VERSION 5.7 ;
  NOWIREEXTENSIONATPIN ON ;
  DIVIDERCHAR "/" ;
  BUSBITCHARS "[]" ;
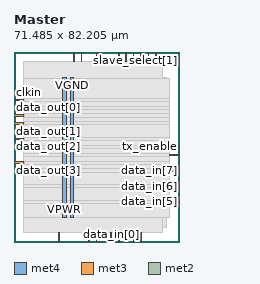
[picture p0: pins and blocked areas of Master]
MACRO Master
  CLASS BLOCK ;
  FOREIGN Master ;
  ORIGIN 0.000 0.000 ;
  SIZE 71.485 BY 82.205 ;
  PIN VGND
    DIRECTION INOUT ;
    USE GROUND ;
    PORT
      LAYER met4 ;
        RECT 24.340 10.640 25.940 70.960 ;
    END
  END VGND
  PIN VPWR
    DIRECTION INOUT ;
    USE POWER ;
    PORT
      LAYER met4 ;
        RECT 21.040 10.640 22.640 70.960 ;
    END
  END VPWR
  PIN clkin
    DIRECTION INPUT ;
    USE SIGNAL ;
    ANTENNAGATEAREA 0.852000 ;
    PORT
      LAYER met3 ;
        RECT 0.000 61.240 4.000 61.840 ;
    END
  END clkin
  PIN data_in[0]
    DIRECTION INPUT ;
    USE SIGNAL ;
    ANTENNAGATEAREA 0.196500 ;
    PORT
      LAYER met2 ;
        RECT 41.950 0.000 42.230 4.000 ;
    END
  END data_in[0]
  PIN data_in[1]
    DIRECTION INPUT ;
    USE SIGNAL ;
    ANTENNAGATEAREA 0.196500 ;
    PORT
      LAYER met2 ;
        RECT 51.610 0.000 51.890 4.000 ;
    END
  END data_in[1]
  PIN data_in[2]
    DIRECTION INPUT ;
    USE SIGNAL ;
    ANTENNAGATEAREA 0.196500 ;
    PORT
      LAYER met2 ;
        RECT 45.170 0.000 45.450 4.000 ;
    END
  END data_in[2]
  PIN data_in[3]
    DIRECTION INPUT ;
    USE SIGNAL ;
    ANTENNAGATEAREA 0.196500 ;
    PORT
      LAYER met2 ;
        RECT 48.390 0.000 48.670 4.000 ;
    END
  END data_in[3]
  PIN data_in[4]
    DIRECTION INPUT ;
    USE SIGNAL ;
    ANTENNAGATEAREA 0.196500 ;
    PORT
      LAYER met2 ;
        RECT 54.830 0.000 55.110 4.000 ;
    END
  END data_in[4]
  PIN data_in[5]
    DIRECTION INPUT ;
    USE SIGNAL ;
    ANTENNAGATEAREA 0.196500 ;
    PORT
      LAYER met3 ;
        RECT 67.485 17.040 71.485 17.640 ;
    END
  END data_in[5]
  PIN data_in[6]
    DIRECTION INPUT ;
    USE SIGNAL ;
    ANTENNAGATEAREA 0.196500 ;
    PORT
      LAYER met3 ;
        RECT 67.485 23.840 71.485 24.440 ;
    END
  END data_in[6]
  PIN data_in[7]
    DIRECTION INPUT ;
    USE SIGNAL ;
    ANTENNAGATEAREA 0.196500 ;
    PORT
      LAYER met3 ;
        RECT 67.485 30.640 71.485 31.240 ;
    END
  END data_in[7]
  PIN data_out[0]
    DIRECTION OUTPUT ;
    USE SIGNAL ;
    ANTENNADIFFAREA 0.445500 ;
    PORT
      LAYER met3 ;
        RECT 0.000 57.840 4.000 58.440 ;
    END
  END data_out[0]
  PIN data_out[1]
    DIRECTION OUTPUT ;
    USE SIGNAL ;
    ANTENNADIFFAREA 0.445500 ;
    PORT
      LAYER met3 ;
        RECT 0.000 44.240 4.000 44.840 ;
    END
  END data_out[1]
  PIN data_out[2]
    DIRECTION OUTPUT ;
    USE SIGNAL ;
    ANTENNADIFFAREA 0.445500 ;
    PORT
      LAYER met3 ;
        RECT 0.000 40.840 4.000 41.440 ;
    END
  END data_out[2]
  PIN data_out[3]
    DIRECTION OUTPUT ;
    USE SIGNAL ;
    ANTENNADIFFAREA 0.445500 ;
    PORT
      LAYER met3 ;
        RECT 0.000 30.640 4.000 31.240 ;
    END
  END data_out[3]
  PIN data_out[4]
    DIRECTION OUTPUT ;
    USE SIGNAL ;
    ANTENNADIFFAREA 0.445500 ;
    PORT
      LAYER met2 ;
        RECT 19.410 0.000 19.690 4.000 ;
    END
  END data_out[4]
  PIN data_out[5]
    DIRECTION OUTPUT ;
    USE SIGNAL ;
    ANTENNADIFFAREA 0.445500 ;
    PORT
      LAYER met3 ;
        RECT 0.000 34.040 4.000 34.640 ;
    END
  END data_out[5]
  PIN data_out[6]
    DIRECTION OUTPUT ;
    USE SIGNAL ;
    ANTENNADIFFAREA 0.445500 ;
    PORT
      LAYER met2 ;
        RECT 32.290 0.000 32.570 4.000 ;
    END
  END data_out[6]
  PIN data_out[7]
    DIRECTION OUTPUT ;
    USE SIGNAL ;
    ANTENNADIFFAREA 0.445500 ;
    PORT
      LAYER met2 ;
        RECT 35.510 0.000 35.790 4.000 ;
    END
  END data_out[7]
  PIN miso
    DIRECTION INPUT ;
    USE SIGNAL ;
    ANTENNAGATEAREA 0.196500 ;
    PORT
      LAYER met3 ;
        RECT 0.000 54.440 4.000 55.040 ;
    END
  END miso
  PIN mode[0]
    DIRECTION INPUT ;
    USE SIGNAL ;
    ANTENNAGATEAREA 0.196500 ;
    PORT
      LAYER met2 ;
        RECT 25.850 78.205 26.130 82.205 ;
    END
  END mode[0]
  PIN mode[1]
    DIRECTION INPUT ;
    USE SIGNAL ;
    ANTENNAGATEAREA 0.196500 ;
    PORT
      LAYER met2 ;
        RECT 29.070 78.205 29.350 82.205 ;
    END
  END mode[1]
  PIN mosi
    DIRECTION OUTPUT ;
    USE SIGNAL ;
    ANTENNADIFFAREA 0.445500 ;
    PORT
      LAYER met3 ;
        RECT 67.485 37.440 71.485 38.040 ;
    END
  END mosi
  PIN reset
    DIRECTION INPUT ;
    USE SIGNAL ;
    ANTENNAGATEAREA 0.196500 ;
    PORT
      LAYER met3 ;
        RECT 0.000 51.040 4.000 51.640 ;
    END
  END reset
  PIN sclk
    DIRECTION OUTPUT ;
    USE SIGNAL ;
    ANTENNADIFFAREA 0.445500 ;
    PORT
      LAYER met2 ;
        RECT 35.510 78.205 35.790 82.205 ;
    END
  END sclk
  PIN slave_select[0]
    DIRECTION OUTPUT ;
    USE SIGNAL ;
    ANTENNADIFFAREA 0.445500 ;
    PORT
      LAYER met2 ;
        RECT 45.170 78.205 45.450 82.205 ;
    END
  END slave_select[0]
  PIN slave_select[1]
    DIRECTION OUTPUT ;
    USE SIGNAL ;
    ANTENNADIFFAREA 0.445500 ;
    PORT
      LAYER met2 ;
        RECT 61.270 78.205 61.550 82.205 ;
    END
  END slave_select[1]
  PIN slave_select[2]
    DIRECTION OUTPUT ;
    USE SIGNAL ;
    ANTENNADIFFAREA 0.445500 ;
    PORT
      LAYER met2 ;
        RECT 54.830 78.205 55.110 82.205 ;
    END
  END slave_select[2]
  PIN slave_select[3]
    DIRECTION OUTPUT ;
    USE SIGNAL ;
    ANTENNADIFFAREA 0.445500 ;
    PORT
      LAYER met2 ;
        RECT 51.610 78.205 51.890 82.205 ;
    END
  END slave_select[3]
  PIN slave_select_in[0]
    DIRECTION INPUT ;
    USE SIGNAL ;
    ANTENNAGATEAREA 0.196500 ;
    PORT
      LAYER met2 ;
        RECT 58.050 78.205 58.330 82.205 ;
    END
  END slave_select_in[0]
  PIN slave_select_in[1]
    DIRECTION INPUT ;
    USE SIGNAL ;
    ANTENNAGATEAREA 0.196500 ;
    PORT
      LAYER met2 ;
        RECT 48.390 78.205 48.670 82.205 ;
    END
  END slave_select_in[1]
  PIN tx_enable
    DIRECTION INPUT ;
    USE SIGNAL ;
    ANTENNAGATEAREA 0.196500 ;
    PORT
      LAYER met3 ;
        RECT 67.485 40.840 71.485 41.440 ;
    END
  END tx_enable
  OBS
      LAYER nwell ;
        RECT 5.330 10.795 65.970 70.805 ;
      LAYER li1 ;
        RECT 5.520 10.795 65.780 70.805 ;
      LAYER met1 ;
        RECT 4.210 6.160 65.780 70.960 ;
      LAYER met2 ;
        RECT 4.230 77.925 25.570 78.205 ;
        RECT 26.410 77.925 28.790 78.205 ;
        RECT 29.630 77.925 35.230 78.205 ;
        RECT 36.070 77.925 44.890 78.205 ;
        RECT 45.730 77.925 48.110 78.205 ;
        RECT 48.950 77.925 51.330 78.205 ;
        RECT 52.170 77.925 54.550 78.205 ;
        RECT 55.390 77.925 57.770 78.205 ;
        RECT 58.610 77.925 60.990 78.205 ;
        RECT 61.830 77.925 64.310 78.205 ;
        RECT 4.230 4.280 64.310 77.925 ;
        RECT 4.230 4.000 19.130 4.280 ;
        RECT 19.970 4.000 32.010 4.280 ;
        RECT 32.850 4.000 35.230 4.280 ;
        RECT 36.070 4.000 41.670 4.280 ;
        RECT 42.510 4.000 44.890 4.280 ;
        RECT 45.730 4.000 48.110 4.280 ;
        RECT 48.950 4.000 51.330 4.280 ;
        RECT 52.170 4.000 54.550 4.280 ;
        RECT 55.390 4.000 64.310 4.280 ;
      LAYER met3 ;
        RECT 3.990 62.240 67.485 70.885 ;
        RECT 4.400 60.840 67.485 62.240 ;
        RECT 3.990 58.840 67.485 60.840 ;
        RECT 4.400 57.440 67.485 58.840 ;
        RECT 3.990 55.440 67.485 57.440 ;
        RECT 4.400 54.040 67.485 55.440 ;
        RECT 3.990 52.040 67.485 54.040 ;
        RECT 4.400 50.640 67.485 52.040 ;
        RECT 3.990 45.240 67.485 50.640 ;
        RECT 4.400 43.840 67.485 45.240 ;
        RECT 3.990 41.840 67.485 43.840 ;
        RECT 4.400 40.440 67.085 41.840 ;
        RECT 3.990 38.440 67.485 40.440 ;
        RECT 3.990 37.040 67.085 38.440 ;
        RECT 3.990 35.040 67.485 37.040 ;
        RECT 4.400 33.640 67.485 35.040 ;
        RECT 3.990 31.640 67.485 33.640 ;
        RECT 4.400 30.240 67.085 31.640 ;
        RECT 3.990 24.840 67.485 30.240 ;
        RECT 3.990 23.440 67.085 24.840 ;
        RECT 3.990 18.040 67.485 23.440 ;
        RECT 3.990 16.640 67.085 18.040 ;
        RECT 3.990 10.715 67.485 16.640 ;
  END
END Master
END LIBRARY

